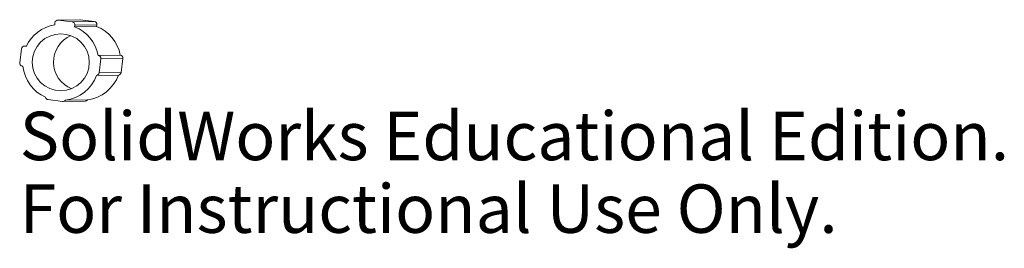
# Model space of a CAD drawing. Units: millimetres. Extents: x -4.1 to 94, y -18.6 to 4.3.
import ezdxf

# ---------------------------------------------------------------- set-up
doc = ezdxf.new("R2010")
doc.units = ezdxf.units.MM
doc.styles.add('SLDTEXTSTYLE0', font='TXT', dxfattribs={"width": 0.7})

msp = doc.modelspace()

# ---------------------------------------------------------------- linework, layer by layer
at = {"color": 7, "linetype": 'Continuous', "lineweight": 15}
for p, q in [((-0.584, 3.954), (-0.609, 3.751)), ((1.904, 4.256), (-0.293, 4.216)), ((1.946, 4.254), (-0.25, 4.214)), ((-0.25, 4.214), (1.135, 4.041)), ((1.135, 4.041), (3.331, 4.08)), ((1.904, 4.256), (1.946, 4.254)), ((1.946, 4.254), (3.331, 4.08)), ((1.395, 3.706), (1.374, 3.541)), ((3.571, 3.581), (1.374, 3.541)), ((3.591, 3.746), (1.395, 3.706)), ((3.591, 3.746), (3.571, 3.581)), ((-4.095, -0.04), (-3.922, 1.349)), ((-3.429, 1.616), (-3.631, 1.612)), ((-3.43, 1.612), (-3.589, 1.61)), ((-3.44, 1.591), (-3.589, 1.61)), ((5.921, 0.732), (3.725, 0.692)), ((3.732, 0.691), (3.725, 0.692)), ((3.732, 0.691), (5.928, 0.731)), ((3.817, -1.042), (3.991, 0.357)), ((6.188, 0.396), (3.991, 0.357)), ((5.928, 0.731), (5.921, 0.732)), ((6.014, -1.002), (6.188, 0.396)), ((-3.769, -0.383), (-3.836, -0.375)), ((5.755, -1.262), (3.559, -1.302)), ((3.817, -1.042), (6.014, -1.002)), ((-1.254, -3.722), (0.178, -3.902)), ((0.221, -3.904), (2.417, -3.864)), ((2.66, -3.732), (0.463, -3.772))]:
    msp.add_line(p, q, dxfattribs=at)
msp.add_circle((-0.001, 0.006), 2.844, dxfattribs=at)
for centre, radius, start, end in [((-0.287, 3.917), 0.299, 82.92768, 172.99422), ((1.097, 3.743), 0.3, 352.82469, 82.75768), ((3.294, 3.783), 0.3, 352.82469, 82.75768), ((0.004, 0.011), 3.789, 99.31012, 155.36088), ((-0.01, 0.005), 3.798, 10.43461, 68.62413), ((2.186, 0.044), 3.798, 10.43461, 68.62413), ((2.121, 0.039), 2.853, 112.98949, 249.09316), ((-3.625, 1.313), 0.299, 82.92768, 172.99422), ((3.694, 0.394), 0.3, 352.82469, 82.75768), ((5.891, 0.434), 0.3, 352.82469, 82.75768), ((-3.798, -0.077), 0.3, 172.82469, 262.75768), ((0.011, -0.003), 3.799, 185.73883, 246.38828), ((-0.004, -0.01), 3.79, 277.08413, 340.0681), ((2.192, 0.03), 3.79, 277.08413, 340.0681), ((3.52, -1.005), 0.3, 277.47083, 352.96763), ((5.717, -0.966), 0.3, 277.47083, 352.96763), ((-1.217, -3.425), 0.299, 191.53506, 262.79174), ((0.215, -3.605), 0.299, 262.87886, 326.18328), ((2.412, -3.565), 0.299, 271.06369, 326.17961)]:
    msp.add_arc(centre, radius, start, end, dxfattribs=at)

# ---------------------------------------------------------------- texts
at = {"color": 7, "linetype": 'Continuous', "char_height": 4.83362, "attachment_point": 1, "style": 'SLDTEXTSTYLE0'}
for s, insert in [('SolidWorks Educational Edition.', (-4.098, -4.924)), ('For Instructional Use Only.', (-4.098, -12.174))]:
    msp.add_mtext(s, dxfattribs=dict(at, insert=insert))

doc.saveas('drawing.dxf')
